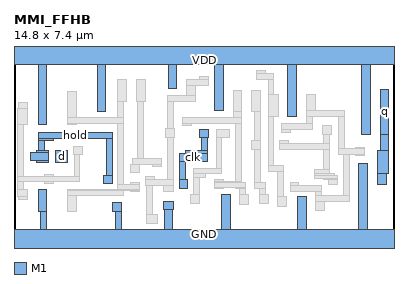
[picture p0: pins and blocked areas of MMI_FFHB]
MACRO MMI_FFHB
	CLASS CORE ;
	FOREIGN MMI_FFHB 0 0 ;
	SIZE 14.8 BY 7.4 ;
	SYMMETRY X Y ;
	SITE CORE1 ;
	PIN d
		DIRECTION input ;
		USE SIGNAL ;
		PORT
			LAYER M1 ;
			RECT 1.625 3.105 2.075 3.555 ;
		END
		AntennaGateArea 0.4968 ;
	END d
	PIN GND
		DIRECTION inout ;
		USE GROUND ;
		PORT
			LAYER M1 ;
			RECT 0.94 1.19 1.28 2.03 ;
			LAYER M1 ;
			RECT 3.83 1.195 4.17 1.535 ;
			LAYER M1 ;
			RECT 5.82 1.255 6.2 1.595 ;
			LAYER M1 ;
			RECT 1.05 0.5 1.28 1.19 ;
			LAYER M1 ;
			RECT 3.94 0.5 4.17 1.195 ;
			LAYER M1 ;
			RECT 5.85 0.5 6.19 1.255 ;
			LAYER M1 ;
			RECT 8.08 0.5 8.42 1.84 ;
			LAYER M1 ;
			RECT 11.04 0.5 11.38 1.755 ;
			LAYER M1 ;
			RECT 13.43 0.5 13.77 3.075 ;
			LAYER M1 ;
			RECT 0 -0.5 14.8 0.5 ;
		END
	END GND
	PIN q
		DIRECTION output ;
		USE SIGNAL ;
		PORT
			LAYER M1 ;
			RECT 14.265 4.19 14.605 5.95 ;
			LAYER M1 ;
			RECT 14.265 3.55 14.595 4.19 ;
			LAYER M1 ;
			RECT 14.15 2.675 14.595 3.55 ;
			LAYER M1 ;
			RECT 14.15 2.235 14.49 2.675 ;
		END
		AntennaDiffArea 1.3248 ;
	END q
	PIN VDD
		DIRECTION inout ;
		USE POWER ;
		PORT
			LAYER M1 ;
			RECT 0 6.9 14.8 7.9 ;
			LAYER M1 ;
			RECT 0.94 4.585 1.28 6.9 ;
			LAYER M1 ;
			RECT 3.24 5.075 3.58 6.9 ;
			LAYER M1 ;
			RECT 6 5.975 6.34 6.9 ;
			LAYER M1 ;
			RECT 7.81 5.105 8.15 6.9 ;
			LAYER M1 ;
			RECT 10.67 4.9 11.01 6.9 ;
			LAYER M1 ;
			RECT 13.545 4.19 13.885 6.9 ;
		END
	END VDD
	PIN clk
		DIRECTION input ;
		USE CLOCK ;
		PORT
			LAYER M1 ;
			RECT 7.24 4.06 7.58 4.4 ;
			LAYER M1 ;
			RECT 7.29 3.57 7.52 4.06 ;
			LAYER M1 ;
			RECT 6.66 3.445 7.52 3.57 ;
			LAYER M1 ;
			RECT 6.43 3.135 7.52 3.445 ;
			LAYER M1 ;
			RECT 6.43 2.415 6.66 3.135 ;
			LAYER M1 ;
			RECT 6.43 2.075 6.77 2.415 ;
		END
		AntennaGateArea 0.6408 ;
	END clk
	PIN hold
		DIRECTION input ;
		USE SIGNAL ;
		PORT
			LAYER M1 ;
			RECT 1.18 4.265 1.52 4.275 ;
			LAYER M1 ;
			RECT 0.95 4.035 3.82 4.265 ;
			LAYER M1 ;
			RECT 0.95 3.935 1.52 4.035 ;
			LAYER M1 ;
			RECT 0.95 3.555 1.18 3.935 ;
			LAYER M1 ;
			RECT 0.875 3.495 1.325 3.555 ;
			LAYER M1 ;
			RECT 0.66 3.155 1.325 3.495 ;
			LAYER M1 ;
			RECT 0.875 3.105 1.325 3.155 ;
			LAYER M1 ;
			RECT 3.59 2.6 3.82 4.035 ;
			LAYER M1 ;
			RECT 3.48 2.26 3.82 2.6 ;
		END
		AntennaGateArea 0.7452 ;
	END hold
	OBS
		LAYER M1 ;
		RECT 0.18 5.21 0.52 5.425 ;
		LAYER M1 ;
		RECT 0.155 4.585 0.52 5.21 ;
		LAYER M1 ;
		RECT 2.09 4.84 2.43 5.865 ;
		LAYER M1 ;
		RECT 4.05 5.475 4.39 6.315 ;
		LAYER M1 ;
		RECT 4.77 5.475 5.11 6.315 ;
		LAYER M1 ;
		RECT 7.24 6.32 7.58 6.43 ;
		LAYER M1 ;
		RECT 6.72 6.09 7.58 6.32 ;
		LAYER M1 ;
		RECT 6.72 5.705 7.06 6.09 ;
		LAYER M1 ;
		RECT 5.97 5.475 7.06 5.705 ;
		LAYER M1 ;
		RECT 4.05 4.84 4.28 5.475 ;
		LAYER M1 ;
		RECT 2.09 4.61 4.28 4.84 ;
		LAYER M1 ;
		RECT 2.09 4.585 2.43 4.61 ;
		LAYER M1 ;
		RECT 0.155 2.57 0.385 4.585 ;
		LAYER M1 ;
		RECT 2.325 3.39 2.665 3.73 ;
		LAYER M1 ;
		RECT 1.18 2.57 1.52 2.625 ;
		LAYER M1 ;
		RECT 2.34 2.57 2.57 3.39 ;
		LAYER M1 ;
		RECT 0.155 2.34 2.57 2.57 ;
		LAYER M1 ;
		RECT 0.155 2.03 0.385 2.34 ;
		LAYER M1 ;
		RECT 1.18 2.285 1.52 2.34 ;
		LAYER M1 ;
		RECT 4.05 2.225 4.28 4.61 ;
		LAYER M1 ;
		RECT 4.795 3.265 5.025 5.475 ;
		LAYER M1 ;
		RECT 5.97 4.425 6.2 5.475 ;
		LAYER M1 ;
		RECT 9.45 6.56 9.79 6.67 ;
		LAYER M1 ;
		RECT 9.45 6.33 10.125 6.56 ;
		LAYER M1 ;
		RECT 8.53 5.075 8.87 5.915 ;
		LAYER M1 ;
		RECT 9.25 5.075 9.59 5.915 ;
		LAYER M1 ;
		RECT 6.57 4.86 6.91 4.865 ;
		LAYER M1 ;
		RECT 8.53 4.86 8.85 5.075 ;
		LAYER M1 ;
		RECT 6.57 4.63 8.85 4.86 ;
		LAYER M1 ;
		RECT 6.57 4.525 6.91 4.63 ;
		LAYER M1 ;
		RECT 5.895 4.085 6.235 4.425 ;
		LAYER M1 ;
		RECT 5.4 3.265 5.74 3.27 ;
		LAYER M1 ;
		RECT 4.615 3.035 5.74 3.265 ;
		LAYER M1 ;
		RECT 4.555 2.695 4.895 3.035 ;
		LAYER M1 ;
		RECT 5.4 2.93 5.74 3.035 ;
		LAYER M1 ;
		RECT 5.135 2.445 5.475 2.555 ;
		LAYER M1 ;
		RECT 5.97 2.445 6.2 4.085 ;
		LAYER M1 ;
		RECT 7.87 4.06 8.39 4.4 ;
		LAYER M1 ;
		RECT 4.555 2.225 4.895 2.315 ;
		LAYER M1 ;
		RECT 4.05 2.03 4.895 2.225 ;
		LAYER M1 ;
		RECT 5.135 2.215 6.2 2.445 ;
		LAYER M1 ;
		RECT 0.155 1.755 0.52 2.03 ;
		LAYER M1 ;
		RECT 0.18 1.65 0.52 1.755 ;
		LAYER M1 ;
		RECT 2.09 1.995 4.895 2.03 ;
		LAYER M1 ;
		RECT 2.09 1.8 4.28 1.995 ;
		LAYER M1 ;
		RECT 4.555 1.975 4.895 1.995 ;
		LAYER M1 ;
		RECT 2.09 1.19 2.43 1.8 ;
		LAYER M1 ;
		RECT 5.18 1.08 5.41 2.215 ;
		LAYER M1 ;
		RECT 5.82 1.975 6.2 2.215 ;
		LAYER M1 ;
		RECT 7.87 2.88 8.1 4.06 ;
		LAYER M1 ;
		RECT 7 2.65 8.1 2.88 ;
		LAYER M1 ;
		RECT 7 2.505 7.44 2.65 ;
		LAYER M1 ;
		RECT 7 1.84 7.23 2.505 ;
		LAYER M1 ;
		RECT 7.8 2.355 8.14 2.415 ;
		LAYER M1 ;
		RECT 8.62 2.355 8.85 4.63 ;
		LAYER M1 ;
		RECT 9.36 3.95 9.59 5.075 ;
		LAYER M1 ;
		RECT 9.25 3.61 9.59 3.95 ;
		LAYER M1 ;
		RECT 7.8 2.305 8.875 2.355 ;
		LAYER M1 ;
		RECT 9.36 2.315 9.59 3.61 ;
		LAYER M1 ;
		RECT 9.895 5.74 10.125 6.33 ;
		LAYER M1 ;
		RECT 9.895 4.9 10.29 5.74 ;
		LAYER M1 ;
		RECT 11.39 5.13 11.73 5.74 ;
		LAYER M1 ;
		RECT 11.39 4.9 12.885 5.13 ;
		LAYER M1 ;
		RECT 9.895 2.965 10.125 4.9 ;
		LAYER M1 ;
		RECT 11.39 4.62 11.62 4.9 ;
		LAYER M1 ;
		RECT 10.43 4.39 11.62 4.62 ;
		LAYER M1 ;
		RECT 10.43 4.28 10.77 4.39 ;
		LAYER M1 ;
		RECT 12.03 4.19 12.37 4.53 ;
		LAYER M1 ;
		RECT 10.355 3.84 10.695 3.95 ;
		LAYER M1 ;
		RECT 12.05 3.84 12.28 4.19 ;
		LAYER M1 ;
		RECT 10.355 3.61 12.28 3.84 ;
		LAYER M1 ;
		RECT 9.895 2.735 10.51 2.965 ;
		LAYER M1 ;
		RECT 12.05 2.805 12.28 3.61 ;
		LAYER M1 ;
		RECT 12.655 3.635 12.885 4.9 ;
		LAYER M1 ;
		RECT 13.31 3.635 13.65 3.69 ;
		LAYER M1 ;
		RECT 12.655 3.405 13.65 3.635 ;
		LAYER M1 ;
		RECT 7.8 2.125 9.03 2.305 ;
		LAYER M1 ;
		RECT 7.8 2.075 8.14 2.125 ;
		LAYER M1 ;
		RECT 8.62 2.075 9.03 2.125 ;
		LAYER M1 ;
		RECT 9.36 2.085 9.79 2.315 ;
		LAYER M1 ;
		RECT 8.8 1.84 9.03 2.075 ;
		LAYER M1 ;
		RECT 9.56 1.84 9.79 2.085 ;
		LAYER M1 ;
		RECT 6.89 1.5 7.23 1.84 ;
		LAYER M1 ;
		RECT 5.18 0.74 5.585 1.08 ;
		LAYER M1 ;
		RECT 8.8 1.46 9.14 1.84 ;
		LAYER M1 ;
		RECT 9.56 1.5 9.9 1.84 ;
		LAYER M1 ;
		RECT 10.28 1.755 10.51 2.735 ;
		LAYER M1 ;
		RECT 11.715 2.675 12.28 2.805 ;
		LAYER M1 ;
		RECT 11.715 2.575 12.495 2.675 ;
		LAYER M1 ;
		RECT 11.715 2.465 12.58 2.575 ;
		LAYER M1 ;
		RECT 12.05 2.445 12.58 2.465 ;
		LAYER M1 ;
		RECT 10.76 2.215 11.1 2.325 ;
		LAYER M1 ;
		RECT 12.24 2.235 12.58 2.445 ;
		LAYER M1 ;
		RECT 10.76 1.985 11.99 2.215 ;
		LAYER M1 ;
		RECT 11.76 1.8 11.99 1.985 ;
		LAYER M1 ;
		RECT 12.82 1.8 13.05 3.405 ;
		LAYER M1 ;
		RECT 13.31 3.35 13.65 3.405 ;
		LAYER M1 ;
		RECT 10.28 1.375 10.62 1.755 ;
		LAYER M1 ;
		RECT 11.76 1.57 13.05 1.8 ;
		LAYER M1 ;
		RECT 11.76 1.215 12.1 1.57 ;
	END
END MMI_FFHB
